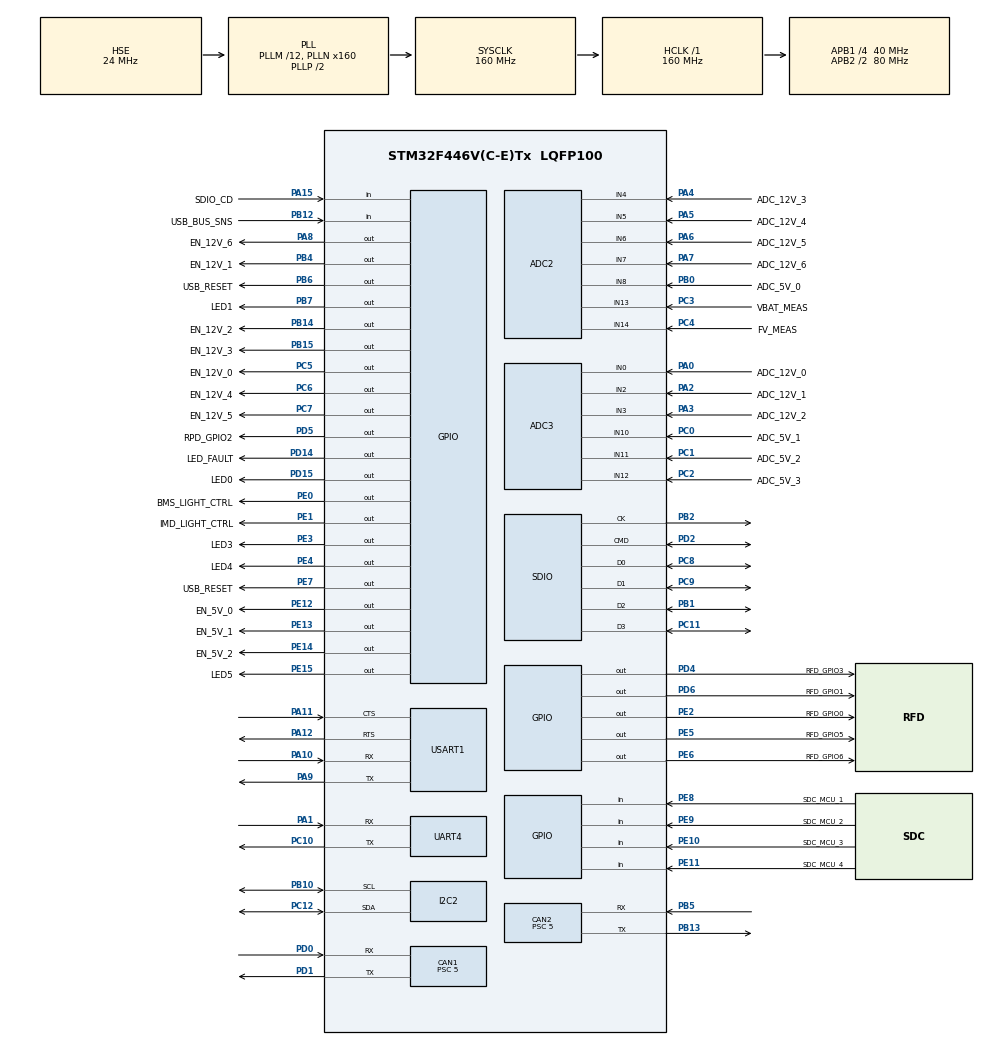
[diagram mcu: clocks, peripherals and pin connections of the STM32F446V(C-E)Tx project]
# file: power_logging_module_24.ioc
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ADC1.Channel-0\#ChannelRegularConversion=ADC_CHANNEL_TEMPSENSOR
ADC1.ClockPrescaler=ADC_CLOCK_SYNC_PCLK_DIV8
ADC1.ContinuousConvMode=ENABLE
ADC1.DMAContinuousRequests=ENABLE
ADC1.DiscontinuousConvMode=DISABLE
ADC1.ExternalTrigConv=ADC_EXTERNALTRIGCONV_T3_TRGO
ADC1.NbrOfConversionFlag=1
ADC1.Rank-0\#ChannelRegularConversion=1
ADC1.SamplingTime-0\#ChannelRegularConversion=ADC_SAMPLETIME_480CYCLES
ADC1.ScanConvMode=ENABLE
ADC1.master=1
ADC2.Channel-0\#ChannelRegularConversion=ADC_CHANNEL_4
ADC2.Channel-1\#ChannelRegularConversion=ADC_CHANNEL_5
ADC2.Channel-2\#ChannelRegularConversion=ADC_CHANNEL_6
ADC2.Channel-3\#ChannelRegularConversion=ADC_CHANNEL_7
ADC2.Channel-4\#ChannelRegularConversion=ADC_CHANNEL_8
ADC2.Channel-5\#ChannelRegularConversion=ADC_CHANNEL_13
ADC2.Channel-6\#ChannelRegularConversion=ADC_CHANNEL_14
ADC2.ClockPrescaler=ADC_CLOCK_SYNC_PCLK_DIV8
ADC2.ContinuousConvMode=ENABLE
ADC2.DMAContinuousRequests=ENABLE
ADC2.NbrOfConversion=7
ADC2.NbrOfConversionFlag=1
ADC2.Rank-0\#ChannelRegularConversion=1
ADC2.Rank-1\#ChannelRegularConversion=2
ADC2.Rank-2\#ChannelRegularConversion=3
ADC2.Rank-3\#ChannelRegularConversion=4
ADC2.Rank-4\#ChannelRegularConversion=5
ADC2.Rank-5\#ChannelRegularConversion=6
ADC2.Rank-6\#ChannelRegularConversion=7
ADC2.SamplingTime-0\#ChannelRegularConversion=ADC_SAMPLETIME_480CYCLES
ADC2.SamplingTime-1\#ChannelRegularConversion=ADC_SAMPLETIME_480CYCLES
ADC2.SamplingTime-2\#ChannelRegularConversion=ADC_SAMPLETIME_480CYCLES
ADC2.SamplingTime-3\#ChannelRegularConversion=ADC_SAMPLETIME_480CYCLES
ADC2.SamplingTime-4\#ChannelRegularConversion=ADC_SAMPLETIME_480CYCLES
ADC2.SamplingTime-5\#ChannelRegularConversion=ADC_SAMPLETIME_480CYCLES
ADC2.SamplingTime-6\#ChannelRegularConversion=ADC_SAMPLETIME_480CYCLES
ADC2.ScanConvMode=ENABLE
ADC3.Channel-0\#ChannelRegularConversion=ADC_CHANNEL_0
ADC3.Channel-1\#ChannelRegularConversion=ADC_CHANNEL_2
ADC3.Channel-2\#ChannelRegularConversion=ADC_CHANNEL_3
ADC3.Channel-3\#ChannelRegularConversion=ADC_CHANNEL_10
ADC3.Channel-4\#ChannelRegularConversion=ADC_CHANNEL_11
ADC3.Channel-5\#ChannelRegularConversion=ADC_CHANNEL_12
ADC3.ClockPrescaler=ADC_CLOCK_SYNC_PCLK_DIV8
ADC3.ContinuousConvMode=ENABLE
ADC3.DMAContinuousRequests=ENABLE
ADC3.NbrOfConversion=6
ADC3.NbrOfConversionFlag=1
ADC3.Rank-0\#ChannelRegularConversion=1
ADC3.Rank-1\#ChannelRegularConversion=2
ADC3.Rank-2\#ChannelRegularConversion=3
ADC3.Rank-3\#ChannelRegularConversion=4
ADC3.Rank-4\#ChannelRegularConversion=5
ADC3.Rank-5\#ChannelRegularConversion=6
ADC3.SamplingTime-0\#ChannelRegularConversion=ADC_SAMPLETIME_480CYCLES
ADC3.SamplingTime-1\#ChannelRegularConversion=ADC_SAMPLETIME_480CYCLES
ADC3.SamplingTime-2\#ChannelRegularConversion=ADC_SAMPLETIME_480CYCLES
ADC3.SamplingTime-3\#ChannelRegularConversion=ADC_SAMPLETIME_480CYCLES
ADC3.SamplingTime-4\#ChannelRegularConversion=ADC_SAMPLETIME_480CYCLES
ADC3.SamplingTime-5\#ChannelRegularConversion=ADC_SAMPLETIME_480CYCLES
ADC3.ScanConvMode=ENABLE
CAN1.ABOM=DISABLE
CAN1.AWUM=DISABLE
CAN1.BS1=CAN_BS1_6TQ
CAN1.CalculateBaudRate=1000000
CAN1.CalculateTimeBit=1000
CAN1.CalculateTimeQuantum=125.0
CAN1.Prescaler=5
CAN2.ABOM=DISABLE
CAN2.AWUM=DISABLE
CAN2.BS1=CAN_BS1_6TQ
CAN2.CalculateBaudRate=1000000
CAN2.CalculateTimeBit=1000
CAN2.CalculateTimeQuantum=125.0
CAN2.Prescaler=5
Dma.ADC1.2.Direction=DMA_PERIPH_TO_MEMORY
Dma.ADC1.2.FIFOMode=DMA_FIFOMODE_DISABLE
Dma.ADC1.2.Instance=DMA2_Stream0
Dma.ADC1.2.MemDataAlignment=DMA_MDATAALIGN_HALFWORD
Dma.ADC1.2.MemInc=DMA_MINC_ENABLE
Dma.ADC1.2.Mode=DMA_CIRCULAR
Dma.ADC1.2.PeriphDataAlignment=DMA_PDATAALIGN_HALFWORD
Dma.ADC1.2.PeriphInc=DMA_PINC_DISABLE
Dma.ADC1.2.Priority=DMA_PRIORITY_LOW
Dma.ADC2.0.Direction=DMA_PERIPH_TO_MEMORY
Dma.ADC2.0.FIFOMode=DMA_FIFOMODE_DISABLE
Dma.ADC2.0.Instance=DMA2_Stream2
Dma.ADC2.0.MemDataAlignment=DMA_MDATAALIGN_HALFWORD
Dma.ADC2.0.MemInc=DMA_MINC_ENABLE
Dma.ADC2.0.Mode=DMA_CIRCULAR
Dma.ADC2.0.PeriphDataAlignment=DMA_PDATAALIGN_HALFWORD
Dma.ADC2.0.PeriphInc=DMA_PINC_DISABLE
Dma.ADC2.0.Priority=DMA_PRIORITY_LOW
Dma.ADC3.1.Direction=DMA_PERIPH_TO_MEMORY
Dma.ADC3.1.FIFOMode=DMA_FIFOMODE_DISABLE
Dma.ADC3.1.Instance=DMA2_Stream1
Dma.ADC3.1.MemDataAlignment=DMA_MDATAALIGN_HALFWORD
Dma.ADC3.1.MemInc=DMA_MINC_ENABLE
Dma.ADC3.1.Mode=DMA_CIRCULAR
Dma.ADC3.1.PeriphDataAlignment=DMA_PDATAALIGN_HALFWORD
Dma.ADC3.1.PeriphInc=DMA_PINC_DISABLE
Dma.ADC3.1.Priority=DMA_PRIORITY_LOW
Dma.Request0=ADC2
Dma.Request1=ADC3
Dma.Request2=ADC1
Dma.Request3=SDIO_RX
Dma.Request4=SDIO_TX
Dma.SDIO_RX.3.Direction=DMA_PERIPH_TO_MEMORY
Dma.SDIO_RX.3.FIFOMode=DMA_FIFOMODE_ENABLE
Dma.SDIO_RX.3.FIFOThreshold=DMA_FIFO_THRESHOLD_FULL
Dma.SDIO_RX.3.Instance=DMA2_Stream3
Dma.SDIO_RX.3.MemBurst=DMA_MBURST_INC4
Dma.SDIO_RX.3.MemDataAlignment=DMA_MDATAALIGN_WORD
Dma.SDIO_RX.3.MemInc=DMA_MINC_ENABLE
Dma.SDIO_RX.3.Mode=DMA_PFCTRL
Dma.SDIO_RX.3.PeriphBurst=DMA_PBURST_INC4
Dma.SDIO_RX.3.PeriphDataAlignment=DMA_PDATAALIGN_WORD
Dma.SDIO_RX.3.PeriphInc=DMA_PINC_DISABLE
Dma.SDIO_RX.3.Priority=DMA_PRIORITY_LOW
Dma.SDIO_TX.4.Direction=DMA_MEMORY_TO_PERIPH
Dma.SDIO_TX.4.FIFOMode=DMA_FIFOMODE_ENABLE
Dma.SDIO_TX.4.FIFOThreshold=DMA_FIFO_THRESHOLD_FULL
Dma.SDIO_TX.4.Instance=DMA2_Stream6
Dma.SDIO_TX.4.MemBurst=DMA_MBURST_INC4
Dma.SDIO_TX.4.MemDataAlignment=DMA_MDATAALIGN_WORD
Dma.SDIO_TX.4.MemInc=DMA_MINC_ENABLE
Dma.SDIO_TX.4.Mode=DMA_PFCTRL
Dma.SDIO_TX.4.PeriphBurst=DMA_PBURST_INC4
Dma.SDIO_TX.4.PeriphDataAlignment=DMA_PDATAALIGN_WORD
Dma.SDIO_TX.4.PeriphInc=DMA_PINC_DISABLE
Dma.SDIO_TX.4.Priority=DMA_PRIORITY_LOW
FREERTOS.Tasks01=service_can,0,1024,plm_task_service_can,Default,NULL,Dynamic,NULL,NULL;store_data,0,1024,plm_task_store_data,Default,NULL,Dynamic,NULL,NULL;plm_heartbeat,-2,512,plm_task_heartbeat,Default,NULL,Dynamic,NULL,NULL;simulate_data,-2,512,plm_task_simulate_data,Default,NULL,Dynamic,NULL,NULL;collect_data,0,1024,plm_task_collect_data,Default,NULL,Dynamic,NULL,NULL;monitor_current,0,1024,plm_task_monitor_current,Default,NULL,Dynamic,NULL,NULL
FREERTOS.configENABLE_FPU=1
FREERTOS.configTOTAL_HEAP_SIZE=64000
FREERTOS.configUSE_NEWLIB_REENTRANT=1
Mcu.Family=STM32F4
Mcu.Name=STM32F446V(C-E)Tx
Mcu.Package=LQFP100
NVIC.ADC_IRQn=true\:5\:0\:true\:false\:true\:true\:true\:true\:true
NVIC.CAN1_RX0_IRQn=true\:5\:0\:true\:false\:true\:true\:true\:true\:true
NVIC.CAN1_RX1_IRQn=true\:5\:0\:true\:false\:true\:true\:true\:true\:true
NVIC.CAN1_TX_IRQn=true\:5\:0\:true\:false\:true\:true\:true\:true\:true
NVIC.CAN2_RX0_IRQn=true\:5\:0\:true\:false\:true\:true\:true\:true\:true
NVIC.CAN2_RX1_IRQn=true\:5\:0\:true\:false\:true\:true\:true\:true\:true
NVIC.CAN2_TX_IRQn=true\:5\:0\:true\:false\:true\:true\:true\:true\:true
NVIC.DMA2_Stream0_IRQn=true\:5\:0\:true\:false\:true\:true\:false\:true\:true
NVIC.DMA2_Stream1_IRQn=true\:5\:0\:true\:false\:true\:true\:false\:true\:true
NVIC.DMA2_Stream2_IRQn=true\:5\:0\:true\:false\:true\:true\:false\:true\:true
NVIC.DMA2_Stream3_IRQn=true\:5\:0\:false\:false\:true\:true\:false\:true\:true
NVIC.DMA2_Stream6_IRQn=true\:5\:0\:false\:false\:true\:true\:false\:true\:true
NVIC.PriorityGroup=NVIC_PRIORITYGROUP_4
NVIC.SDIO_IRQn=true\:5\:0\:false\:false\:true\:true\:true\:true\:true
NVIC.TIM1_UP_TIM10_IRQn=true\:5\:0\:false\:false\:true\:false\:false\:true\:true
NVIC.TIM6_DAC_IRQn=true\:15\:0\:false\:false\:true\:false\:false\:true\:true
NVIC.TimeBase=TIM6_DAC_IRQn
NVIC.TimeBaseIP=TIM6
PA0-WKUP.GPIO_Label=ADC_12V_0
PA0-WKUP.Signal=ADCx_IN0
PA1.Mode=Asynchronous
PA1.Signal=UART4_RX
PA10.Mode=Asynchronous
PA10.Signal=USART1_RX
PA11.Mode=CTS_RTS
PA11.Signal=USART1_CTS
PA12.Mode=CTS_RTS
PA12.Signal=USART1_RTS
PA13.Mode=Serial_Wire
PA13.Signal=SYS_JTMS-SWDIO
PA14.Mode=Serial_Wire
PA14.Signal=SYS_JTCK-SWCLK
PA15.GPIO_Label=SDIO_CD
PA15.Signal=GPIO_Input
PA2.GPIO_Label=ADC_12V_1
PA2.Signal=ADCx_IN2
PA3.GPIO_Label=ADC_12V_2
PA3.Signal=ADCx_IN3
PA4.GPIO_Label=ADC_12V_3
PA4.Signal=ADCx_IN4
PA5.GPIO_Label=ADC_12V_4
PA5.Signal=ADCx_IN5
PA6.GPIO_Label=ADC_12V_5
PA6.Signal=ADCx_IN6
PA7.GPIO_Label=ADC_12V_6
PA7.Signal=ADCx_IN7
PA8.GPIO_Label=EN_12V_6
PA8.Signal=GPIO_Output
PA9.Mode=Asynchronous
PA9.Signal=USART1_TX
PB0.GPIO_Label=ADC_5V_0
PB0.Signal=ADCx_IN8
PB1.Mode=SD_4_bits_Wide_bus
PB1.Signal=SDIO_D2
PB10.Mode=I2C
PB10.Signal=I2C2_SCL
PB12.GPIO_Label=USB_BUS_SNS
PB12.Signal=GPIO_Input
PB13.Mode=CAN_Activate
PB13.Signal=CAN2_TX
PB14.GPIO_Label=EN_12V_2
PB14.Signal=GPIO_Output
PB15.GPIO_Label=EN_12V_3
PB15.Signal=GPIO_Output
PB2.Mode=SD_4_bits_Wide_bus
PB2.Signal=SDIO_CK
PB3.Signal=SYS_JTDO-SWO
PB4.GPIO_Label=EN_12V_1
PB4.Signal=GPIO_Output
PB5.Mode=CAN_Activate
PB5.Signal=CAN2_RX
PB6.GPIO_Label=USB_RESET
PB6.Signal=GPIO_Output
PB7.GPIO_Label=LED1
PB7.Signal=GPIO_Output
PC0.GPIO_Label=ADC_5V_1
PC0.Signal=ADCx_IN10
PC1.GPIO_Label=ADC_5V_2
PC1.Signal=ADCx_IN11
PC10.Mode=Asynchronous
PC10.Signal=UART4_TX
PC11.Mode=SD_4_bits_Wide_bus
PC11.Signal=SDIO_D3
PC12.Mode=I2C
PC12.Signal=I2C2_SDA
PC14-OSC32_IN.Mode=LSE-External-Clock-Source
PC14-OSC32_IN.Signal=RCC_OSC32_IN
PC15-OSC32_OUT.Mode=LSE-External-Clock-Source
PC15-OSC32_OUT.Signal=RCC_OSC32_OUT
PC2.GPIO_Label=ADC_5V_3
PC2.Signal=ADCx_IN12
PC3.GPIO_Label=VBAT_MEAS
PC3.Signal=ADCx_IN13
PC4.GPIO_Label=FV_MEAS
PC4.Signal=ADCx_IN14
PC5.GPIO_Label=EN_12V_0
PC5.Signal=GPIO_Output
PC6.GPIO_Label=EN_12V_4
PC6.Signal=GPIO_Output
PC7.GPIO_Label=EN_12V_5
PC7.Signal=GPIO_Output
PC8.GPIO_PuPd=GPIO_PULLUP
PC8.Mode=SD_4_bits_Wide_bus
PC8.Signal=SDIO_D0
PC9.Mode=SD_4_bits_Wide_bus
PC9.Signal=SDIO_D1
PD0.Mode=CAN_Activate
PD0.Signal=CAN1_RX
PD1.Mode=CAN_Activate
PD1.Signal=CAN1_TX
PD14.GPIO_Label=LED_FAULT
PD14.Signal=GPIO_Output
PD15.GPIO_Label=LED0
PD15.Signal=GPIO_Output
PD2.GPIO_PuPd=GPIO_PULLUP
PD2.Mode=SD_4_bits_Wide_bus
PD2.Signal=SDIO_CMD
PD4.GPIO_Label=RFD_GPIO3
PD4.Signal=GPIO_Output
PD5.GPIO_Label=RPD_GPIO2
PD5.Signal=GPIO_Output
PD6.GPIO_Label=RFD_GPIO1
PD6.Signal=GPIO_Output
PE0.GPIO_Label=BMS_LIGHT_CTRL
PE0.Signal=GPIO_Output
PE1.GPIO_Label=IMD_LIGHT_CTRL
PE1.Signal=GPIO_Output
PE10.GPIO_Label=SDC_MCU_3
PE10.Signal=GPIO_Input
PE11.GPIO_Label=SDC_MCU_4
PE11.Signal=GPIO_Input
PE12.GPIO_Label=EN_5V_0
PE12.Signal=GPIO_Output
PE13.GPIO_Label=EN_5V_1
PE13.Signal=GPIO_Output
PE14.GPIO_Label=EN_5V_2
PE14.Signal=GPIO_Output
PE15.GPIO_Label=LED5
PE15.Signal=GPIO_Output
PE2.GPIO_Label=RFD_GPIO0
PE2.Signal=GPIO_Output
PE3.GPIO_Label=LED3
PE3.Signal=GPIO_Output
PE4.GPIO_Label=LED4
PE4.Signal=GPIO_Output
PE5.GPIO_Label=RFD_GPIO5
PE5.Signal=GPIO_Output
PE6.GPIO_Label=RFD_GPIO6
PE6.Signal=GPIO_Output
PE7.GPIO_Label=USB_RESET
PE7.Signal=GPIO_Output
PE8.GPIO_Label=SDC_MCU_1
PE8.Signal=GPIO_Input
PE9.GPIO_Label=SDC_MCU_2
PE9.Signal=GPIO_Input
PH0-OSC_IN.Mode=HSE-External-Clock-Source
PH0-OSC_IN.Signal=RCC_OSC_IN
PH1-OSC_OUT.Mode=HSE-External-Clock-Source
PH1-OSC_OUT.Signal=RCC_OSC_OUT
ProjectManager.HeapSize=0x80
ProjectManager.StackSize=0x400
ProjectManager.TargetToolchain=STM32CubeIDE
RCC.AHBFreq_Value=160000000
RCC.APB1CLKDivider=RCC_HCLK_DIV4
RCC.APB1Freq_Value=40000000
RCC.APB1TimFreq_Value=80000000
RCC.APB2CLKDivider=RCC_HCLK_DIV2
RCC.APB2Freq_Value=80000000
RCC.APB2TimFreq_Value=160000000
RCC.CortexFreq_Value=160000000
RCC.HCLKFreq_Value=160000000
RCC.HSE_VALUE=24000000
RCC.PLLM=12
RCC.PLLN=160
RCC.PLLQ=7
RCC.PLLSourceVirtual=RCC_PLLSOURCE_HSE
RCC.RCC_RTC_Clock_SourceVirtual=RCC_RTCCLKSOURCE_LSE
RCC.SYSCLKFreq_VALUE=160000000
RCC.SYSCLKSource=RCC_SYSCLKSOURCE_PLLCLK
RCC.USBFreq_Value=45714285.71428572
RCC.VCOOutputFreq_Value=320000000
SH.ADCx_IN0.0=ADC3_IN0,IN0
SH.ADCx_IN10.0=ADC3_IN10,IN10
SH.ADCx_IN11.0=ADC3_IN11,IN11
SH.ADCx_IN12.0=ADC3_IN12,IN12
SH.ADCx_IN13.0=ADC2_IN13,IN13
SH.ADCx_IN14.0=ADC2_IN14,IN14
SH.ADCx_IN2.0=ADC3_IN2,IN2
SH.ADCx_IN3.0=ADC3_IN3,IN3
SH.ADCx_IN4.0=ADC2_IN4,IN4
SH.ADCx_IN5.0=ADC2_IN5,IN5
SH.ADCx_IN6.0=ADC2_IN6,IN6
SH.ADCx_IN7.0=ADC2_IN7,IN7
SH.ADCx_IN8.0=ADC2_IN8,IN8
TIM3.Period=10000-1
TIM3.Prescaler=840-1
TIM3.TIM_MasterOutputTrigger=TIM_TRGO_UPDATE
UART4.VirtualMode=Asynchronous
USART1.VirtualMode=VM_ASYNC
VP_ADC1_TempSens_Input.Mode=IN-TempSens
VP_FREERTOS_VS_CMSIS_V1.Mode=CMSIS_V1
VP_RTC_VS_RTC_Activate.Mode=RTC_Enabled
VP_SYS_VS_tim6.Mode=TIM6
VP_TIM10_VS_ClockSourceINT.Mode=Enable_Timer
VP_TIM3_VS_ClockSourceINT.Mode=Internal
board=custom

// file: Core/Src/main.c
/* USER CODE BEGIN Header */
/**
  ******************************************************************************
  * @file           : main.c
  * @brief          : Main program body
  ******************************************************************************
  * @attention
  *
  * Copyright (c) 2024 STMicroelectronics.
  * All rights reserved.
  *
  * This software is licensed under terms that can be found in the LICENSE file
  * in the root directory of this software component.
  * If no LICENSE file comes with this software, it is provided AS-IS.
  *
  ******************************************************************************
  */
/* USER CODE END Header */
#include "main.h"
#include "cmsis_os.h"
#include "fatfs.h"

/* USER CODE BEGIN Includes */
#include <stdio.h>
#include "plm.h"
#include "adc_lib.h"
#include "plm_error.h"
/* USER CODE END Includes */

ADC_HandleTypeDef hadc1;
ADC_HandleTypeDef hadc2;
ADC_HandleTypeDef hadc3;
DMA_HandleTypeDef hdma_adc1;
DMA_HandleTypeDef hdma_adc2;
DMA_HandleTypeDef hdma_adc3;

CAN_HandleTypeDef hcan1;
CAN_HandleTypeDef hcan2;

I2C_HandleTypeDef hi2c2;

RTC_HandleTypeDef hrtc;

SD_HandleTypeDef hsd;
DMA_HandleTypeDef hdma_sdio_rx;
DMA_HandleTypeDef hdma_sdio_tx;

TIM_HandleTypeDef htim3;
TIM_HandleTypeDef htim10;

UART_HandleTypeDef huart4;
UART_HandleTypeDef huart1;

osThreadId service_canHandle;
osThreadId store_dataHandle;
osThreadId plm_heartbeatHandle;
osThreadId simulate_dataHandle;
osThreadId collect_dataHandle;
osThreadId monitor_currentHandle;

void SystemClock_Config(void);
static void MX_GPIO_Init(void);
static void MX_DMA_Init(void);
static void MX_ADC1_Init(void);
static void MX_ADC2_Init(void);
static void MX_ADC3_Init(void);
static void MX_CAN1_Init(void);
static void MX_CAN2_Init(void);
static void MX_I2C2_Init(void);
static void MX_RTC_Init(void);
static void MX_SDIO_SD_Init(void);
static void MX_UART4_Init(void);
static void MX_USART1_UART_Init(void);
static void MX_TIM3_Init(void);
static void MX_TIM10_Init(void);
void plm_task_service_can(void const * argument);
void plm_task_store_data(void const * argument);
void plm_task_heartbeat(void const * argument);
void plm_task_simulate_data(void const * argument);
void plm_task_collect_data(void const * argument);
void plm_task_monitor_current(void const * argument);

/* USER CODE BEGIN PFP */
// redirect printf to USART (STLink Virtual COM)
// NOTE: output gets flushed at newline \n
#ifdef __GNUC__
#define PUTCHAR_PROTOTYPE int __io_putchar(int ch)
#else
#define PUTCHAR_PROTOTYPE int fputc(int ch, FILE *f)
#endif

PUTCHAR_PROTOTYPE
{
  HAL_UART_Transmit(&huart4, (uint8_t*)&ch, 1, HAL_MAX_DELAY);
  HAL_UART_Transmit(&huart4, (uint8_t*)&ch, 1, HAL_MAX_DELAY);
  return ch;
}
/* USER CODE END PFP */

int main(void)
{

  /* MCU Configuration--------------------------------------------------------*/

  /* Reset of all peripherals, Initializes the Flash interface and the Systick. */
  HAL_Init();

  /* Configure the system clock */
  SystemClock_Config();

  /* USER CODE BEGIN SysInit */
  MX_DMA_Init();
  /* USER CODE END SysInit */

  /* Initialize all configured peripherals */
  MX_GPIO_Init();
  MX_DMA_Init();
  MX_ADC1_Init();
  MX_ADC2_Init();
  MX_ADC3_Init();
  MX_CAN1_Init();
  MX_CAN2_Init();
  MX_I2C2_Init();
  MX_RTC_Init();
  MX_SDIO_SD_Init();
  MX_UART4_Init();
  MX_USART1_UART_Init();
  MX_TIM3_Init();
  MX_TIM10_Init();
  MX_FATFS_Init();
  /* USER CODE BEGIN 2 */
  plm_init();
  /* USER CODE END 2 */

  /* Create the thread(s) */
  /* definition and creation of service_can */
  osThreadDef(service_can, plm_task_service_can, osPriorityNormal, 0, 1024);
  service_canHandle = osThreadCreate(osThread(service_can), NULL);

  /* definition and creation of store_data */
  osThreadDef(store_data, plm_task_store_data, osPriorityNormal, 0, 1024);
  store_dataHandle = osThreadCreate(osThread(store_data), NULL);

  /* definition and creation of plm_heartbeat */
  osThreadDef(plm_heartbeat, plm_task_heartbeat, osPriorityLow, 0, 512);
  plm_heartbeatHandle = osThreadCreate(osThread(plm_heartbeat), NULL);

  /* definition and creation of simulate_data */
  osThreadDef(simulate_data, plm_task_simulate_data, osPriorityLow, 0, 512);
  simulate_dataHandle = osThreadCreate(osThread(simulate_data), NULL);

  /* definition and creation of collect_data */
  osThreadDef(collect_data, plm_task_collect_data, osPriorityNormal, 0, 1024);
  collect_dataHandle = osThreadCreate(osThread(collect_data), NULL);

  /* definition and creation of monitor_current */
  osThreadDef(monitor_current, plm_task_monitor_current, osPriorityNormal, 0, 1024);
  monitor_currentHandle = osThreadCreate(osThread(monitor_current), NULL);

  /* Start scheduler */
  osKernelStart();

  /* We should never get here as control is now taken by the scheduler */

  /* Infinite loop */
  while (1)
  {

  }
}

void SystemClock_Config(void)
{
  RCC_OscInitTypeDef RCC_OscInitStruct = {0};
  RCC_ClkInitTypeDef RCC_ClkInitStruct = {0};

  /** Configure the main internal regulator output voltage
  */
  __HAL_RCC_PWR_CLK_ENABLE();
  __HAL_PWR_VOLTAGESCALING_CONFIG(PWR_REGULATOR_VOLTAGE_SCALE1);

  /** Initializes the RCC Oscillators according to the specified parameters
  * in the RCC_OscInitTypeDef structure.
  */
  RCC_OscInitStruct.OscillatorType = RCC_OSCILLATORTYPE_HSE|RCC_OSCILLATORTYPE_LSE;
  RCC_OscInitStruct.HSEState = RCC_HSE_BYPASS;
  RCC_OscInitStruct.LSEState = RCC_LSE_BYPASS;
  RCC_OscInitStruct.PLL.PLLState = RCC_PLL_ON;
  RCC_OscInitStruct.PLL.PLLSource = RCC_PLLSOURCE_HSE;
  RCC_OscInitStruct.PLL.PLLM = 12;
  RCC_OscInitStruct.PLL.PLLN = 160;
  RCC_OscInitStruct.PLL.PLLP = RCC_PLLP_DIV2;
  RCC_OscInitStruct.PLL.PLLQ = 7;
  RCC_OscInitStruct.PLL.PLLR = 2;
  if (HAL_RCC_OscConfig(&RCC_OscInitStruct) != HAL_OK)
  {
    Error_Handler();
  }

  /** Initializes the CPU, AHB and APB buses clocks
  */
  RCC_ClkInitStruct.ClockType = RCC_CLOCKTYPE_HCLK|RCC_CLOCKTYPE_SYSCLK
                              |RCC_CLOCKTYPE_PCLK1|RCC_CLOCKTYPE_PCLK2;
  RCC_ClkInitStruct.SYSCLKSource = RCC_SYSCLKSOURCE_PLLCLK;
  RCC_ClkInitStruct.AHBCLKDivider = RCC_SYSCLK_DIV1;
  RCC_ClkInitStruct.APB1CLKDivider = RCC_HCLK_DIV4;
  RCC_ClkInitStruct.APB2CLKDivider = RCC_HCLK_DIV2;

  if (HAL_RCC_ClockConfig(&RCC_ClkInitStruct, FLASH_LATENCY_5) != HAL_OK)
  {
    Error_Handler();
  }
}

static void MX_ADC1_Init(void)
{

  ADC_ChannelConfTypeDef sConfig = {0};

  /** Configure the global features of the ADC (Clock, Resolution, Data Alignment and number of conversion)
  */
  hadc1.Instance = ADC1;
  hadc1.Init.ClockPrescaler = ADC_CLOCK_SYNC_PCLK_DIV8;
  hadc1.Init.Resolution = ADC_RESOLUTION_12B;
  hadc1.Init.ScanConvMode = ENABLE;
  hadc1.Init.ContinuousConvMode = ENABLE;
  hadc1.Init.DiscontinuousConvMode = DISABLE;
  hadc1.Init.ExternalTrigConvEdge = ADC_EXTERNALTRIGCONVEDGE_RISING;
  hadc1.Init.ExternalTrigConv = ADC_EXTERNALTRIGCONV_T3_TRGO;
  hadc1.Init.DataAlign = ADC_DATAALIGN_RIGHT;
  hadc1.Init.NbrOfConversion = 1;
  hadc1.Init.DMAContinuousRequests = ENABLE;
  hadc1.Init.EOCSelection = ADC_EOC_SINGLE_CONV;
  if (HAL_ADC_Init(&hadc1) != HAL_OK)
  {
    Error_Handler();
  }

  /** Configure for the selected ADC regular channel its corresponding rank in the sequencer and its sample time.
  */
  sConfig.Channel = ADC_CHANNEL_TEMPSENSOR;
  sConfig.Rank = 1;
  sConfig.SamplingTime = ADC_SAMPLETIME_480CYCLES;
  if (HAL_ADC_ConfigChannel(&hadc1, &sConfig) != HAL_OK)
  {
    Error_Handler();
  }

}

static void MX_ADC2_Init(void)
{

  ADC_ChannelConfTypeDef sConfig = {0};

  /** Configure the global features of the ADC (Clock, Resolution, Data Alignment and number of conversion)
  */
  hadc2.Instance = ADC2;
  hadc2.Init.ClockPrescaler = ADC_CLOCK_SYNC_PCLK_DIV8;
  hadc2.Init.Resolution = ADC_RESOLUTION_12B;
  hadc2.Init.ScanConvMode = ENABLE;
  hadc2.Init.ContinuousConvMode = ENABLE;
  hadc2.Init.DiscontinuousConvMode = DISABLE;
  hadc2.Init.ExternalTrigConvEdge = ADC_EXTERNALTRIGCONVEDGE_NONE;
  hadc2.Init.ExternalTrigConv = ADC_SOFTWARE_START;
  hadc2.Init.DataAlign = ADC_DATAALIGN_RIGHT;
  hadc2.Init.NbrOfConversion = 7;
  hadc2.Init.DMAContinuousRequests = ENABLE;
  hadc2.Init.EOCSelection = ADC_EOC_SINGLE_CONV;
  if (HAL_ADC_Init(&hadc2) != HAL_OK)
  {
    Error_Handler();
  }

  /** Configure for the selected ADC regular channel its corresponding rank in the sequencer and its sample time.
  */
  sConfig.Channel = ADC_CHANNEL_4;
  sConfig.Rank = 1;
  sConfig.SamplingTime = ADC_SAMPLETIME_480CYCLES;
  if (HAL_ADC_ConfigChannel(&hadc2, &sConfig) != HAL_OK)
  {
    Error_Handler();
  }

  /** Configure for the selected ADC regular channel its corresponding rank in the sequencer and its sample time.
  */
  sConfig.Channel = ADC_CHANNEL_5;
  sConfig.Rank = 2;
  if (HAL_ADC_ConfigChannel(&hadc2, &sConfig) != HAL_OK)
  {
    Error_Handler();
  }

  /** Configure for the selected ADC regular channel its corresponding rank in the sequencer and its sample time.
  */
  sConfig.Channel = ADC_CHANNEL_6;
  sConfig.Rank = 3;
  if (HAL_ADC_ConfigChannel(&hadc2, &sConfig) != HAL_OK)
  {
    Error_Handler();
  }

  /** Configure for the selected ADC regular channel its corresponding rank in the sequencer and its sample time.
  */
  sConfig.Channel = ADC_CHANNEL_7;
  sConfig.Rank = 4;
  if (HAL_ADC_ConfigChannel(&hadc2, &sConfig) != HAL_OK)
  {
    Error_Handler();
  }

  /** Configure for the selected ADC regular channel its corresponding rank in the sequencer and its sample time.
  */
  sConfig.Channel = ADC_CHANNEL_8;
  sConfig.Rank = 5;
  if (HAL_ADC_ConfigChannel(&hadc2, &sConfig) != HAL_OK)
  {
    Error_Handler();
  }

  /** Configure for the selected ADC regular channel its corresponding rank in the sequencer and its sample time.
  */
  sConfig.Channel = ADC_CHANNEL_13;
  sConfig.Rank = 6;
  if (HAL_ADC_ConfigChannel(&hadc2, &sConfig) != HAL_OK)
  {
    Error_Handler();
  }

  /** Configure for the selected ADC regular channel its corresponding rank in the sequencer and its sample time.
  */
  sConfig.Channel = ADC_CHANNEL_14;
  sConfig.Rank = 7;
  if (HAL_ADC_ConfigChannel(&hadc2, &sConfig) != HAL_OK)
  {
    Error_Handler();
  }

}

static void MX_ADC3_Init(void)
{

  ADC_ChannelConfTypeDef sConfig = {0};

  /** Configure the global features of the ADC (Clock, Resolution, Data Alignment and number of conversion)
  */
  hadc3.Instance = ADC3;
  hadc3.Init.ClockPrescaler = ADC_CLOCK_SYNC_PCLK_DIV8;
  hadc3.Init.Resolution = ADC_RESOLUTION_12B;
  hadc3.Init.ScanConvMode = ENABLE;
  hadc3.Init.ContinuousConvMode = ENABLE;
  hadc3.Init.DiscontinuousConvMode = DISABLE;
  hadc3.Init.ExternalTrigConvEdge = ADC_EXTERNALTRIGCONVEDGE_NONE;
  hadc3.Init.ExternalTrigConv = ADC_SOFTWARE_START;
  hadc3.Init.DataAlign = ADC_DATAALIGN_RIGHT;
  hadc3.Init.NbrOfConversion = 6;
  hadc3.Init.DMAContinuousRequests = ENABLE;
  hadc3.Init.EOCSelection = ADC_EOC_SINGLE_CONV;
  if (HAL_ADC_Init(&hadc3) != HAL_OK)
  {
    Error_Handler();
  }

  /** Configure for the selected ADC regular channel its corresponding rank in the sequencer and its sample time.
  */
  sConfig.Channel = ADC_CHANNEL_0;
  sConfig.Rank = 1;
  sConfig.SamplingTime = ADC_SAMPLETIME_480CYCLES;
  if (HAL_ADC_ConfigChannel(&hadc3, &sConfig) != HAL_OK)
  {
    Error_Handler();
  }

  /** Configure for the selected ADC regular channel its corresponding rank in the sequencer and its sample time.
  */
  sConfig.Channel = ADC_CHANNEL_2;
  sConfig.Rank = 2;
  if (HAL_ADC_ConfigChannel(&hadc3, &sConfig) != HAL_OK)
  {
    Error_Handler();
  }

  /** Configure for the selected ADC regular channel its corresponding rank in the sequencer and its sample time.
  */
  sConfig.Channel = ADC_CHANNEL_3;
  sConfig.Rank = 3;
  if (HAL_ADC_ConfigChannel(&hadc3, &sConfig) != HAL_OK)
  {
    Error_Handler();
  }

  /** Configure for the selected ADC regular channel its corresponding rank in the sequencer and its sample time.
  */
  sConfig.Channel = ADC_CHANNEL_10;
  sConfig.Rank = 4;
  if (HAL_ADC_ConfigChannel(&hadc3, &sConfig) != HAL_OK)
  {
    Error_Handler();
  }

  /** Configure for the selected ADC regular channel its corresponding rank in the sequencer and its sample time.
  */
  sConfig.Channel = ADC_CHANNEL_11;
  sConfig.Rank = 5;
  if (HAL_ADC_ConfigChannel(&hadc3, &sConfig) != HAL_OK)
  {
    Error_Handler();
  }

  /** Configure for the selected ADC regular channel its corresponding rank in the sequencer and its sample time.
  */
  sConfig.Channel = ADC_CHANNEL_12;
  sConfig.Rank = 6;
  if (HAL_ADC_ConfigChannel(&hadc3, &sConfig) != HAL_OK)
  {
    Error_Handler();
  }

}

static void MX_CAN1_Init(void)
{

  hcan1.Instance = CAN1;
  hcan1.Init.Prescaler = 5;
  hcan1.Init.Mode = CAN_MODE_NORMAL;
  hcan1.Init.SyncJumpWidth = CAN_SJW_1TQ;
  hcan1.Init.TimeSeg1 = CAN_BS1_6TQ;
  hcan1.Init.TimeSeg2 = CAN_BS2_1TQ;
  hcan1.Init.TimeTriggeredMode = DISABLE;
  hcan1.Init.AutoBusOff = DISABLE;
  hcan1.Init.AutoWakeUp = DISABLE;
  hcan1.Init.AutoRetransmission = DISABLE;
  hcan1.Init.ReceiveFifoLocked = DISABLE;
  hcan1.Init.TransmitFifoPriority = DISABLE;
  if (HAL_CAN_Init(&hcan1) != HAL_OK)
  {
    Error_Handler();
  }

}

static void MX_CAN2_Init(void)
{

  hcan2.Instance = CAN2;
  hcan2.Init.Prescaler = 5;
  hcan2.Init.Mode = CAN_MODE_NORMAL;
  hcan2.Init.SyncJumpWidth = CAN_SJW_1TQ;
  hcan2.Init.TimeSeg1 = CAN_BS1_6TQ;
  hcan2.Init.TimeSeg2 = CAN_BS2_1TQ;
  hcan2.Init.TimeTriggeredMode = DISABLE;
  hcan2.Init.AutoBusOff = DISABLE;
  hcan2.Init.AutoWakeUp = DISABLE;
  hcan2.Init.AutoRetransmission = DISABLE;
  hcan2.Init.ReceiveFifoLocked = DISABLE;
  hcan2.Init.TransmitFifoPriority = DISABLE;
  if (HAL_CAN_Init(&hcan2) != HAL_OK)
  {
    Error_Handler();
  }

}

static void MX_I2C2_Init(void)
{

  hi2c2.Instance = I2C2;
  hi2c2.Init.ClockSpeed = 100000;
  hi2c2.Init.DutyCycle = I2C_DUTYCYCLE_2;
  hi2c2.Init.OwnAddress1 = 0;
  hi2c2.Init.AddressingMode = I2C_ADDRESSINGMODE_7BIT;
  hi2c2.Init.DualAddressMode = I2C_DUALADDRESS_DISABLE;
  hi2c2.Init.OwnAddress2 = 0;
  hi2c2.Init.GeneralCallMode = I2C_GENERALCALL_DISABLE;
  hi2c2.Init.NoStretchMode = I2C_NOSTRETCH_DISABLE;
  if (HAL_I2C_Init(&hi2c2) != HAL_OK)
  {
    Error_Handler();
  }

}

static void MX_RTC_Init(void)
{

  /** Initialize RTC Only
  */
  hrtc.Instance = RTC;
  hrtc.Init.HourFormat = RTC_HOURFORMAT_24;
  hrtc.Init.AsynchPrediv = 127;
  hrtc.Init.SynchPrediv = 255;
  hrtc.Init.OutPut = RTC_OUTPUT_DISABLE;
  hrtc.Init.OutPutPolarity = RTC_OUTPUT_POLARITY_HIGH;
  hrtc.Init.OutPutType = RTC_OUTPUT_TYPE_OPENDRAIN;
  if (HAL_RTC_Init(&hrtc) != HAL_OK)
  {
    Error_Handler();
  }

}

static void MX_SDIO_SD_Init(void)
{

  hsd.Instance = SDIO;
  hsd.Init.ClockEdge = SDIO_CLOCK_EDGE_RISING;
  hsd.Init.ClockBypass = SDIO_CLOCK_BYPASS_DISABLE;
  hsd.Init.ClockPowerSave = SDIO_CLOCK_POWER_SAVE_DISABLE;
  hsd.Init.BusWide = SDIO_BUS_WIDE_4B;
  hsd.Init.HardwareFlowControl = SDIO_HARDWARE_FLOW_CONTROL_DISABLE;
  hsd.Init.ClockDiv = 0;

}

static void MX_TIM3_Init(void)
{

  TIM_ClockConfigTypeDef sClockSourceConfig = {0};
  TIM_MasterConfigTypeDef sMasterConfig = {0};

  htim3.Instance = TIM3;
  htim3.Init.Prescaler = 840-1;
  htim3.Init.CounterMode = TIM_COUNTERMODE_UP;
  htim3.Init.Period = 10000-1;
  htim3.Init.ClockDivision = TIM_CLOCKDIVISION_DIV1;
  htim3.Init.AutoReloadPreload = TIM_AUTORELOAD_PRELOAD_DISABLE;
  if (HAL_TIM_Base_Init(&htim3) != HAL_OK)
  {
    Error_Handler();
  }
  sClockSourceConfig.ClockSource = TIM_CLOCKSOURCE_INTERNAL;
  if (HAL_TIM_ConfigClockSource(&htim3, &sClockSourceConfig) != HAL_OK)
  {
    Error_Handler();
  }
  sMasterConfig.MasterOutputTrigger = TIM_TRGO_UPDATE;
  sMasterConfig.MasterSlaveMode = TIM_MASTERSLAVEMODE_DISABLE;
  if (HAL_TIMEx_MasterConfigSynchronization(&htim3, &sMasterConfig) != HAL_OK)
  {
    Error_Handler();
  }

}

static void MX_TIM10_Init(void)
{

  htim10.Instance = TIM10;
  htim10.Init.Prescaler = 0;
  htim10.Init.CounterMode = TIM_COUNTERMODE_UP;
  htim10.Init.Period = 65535;
  htim10.Init.ClockDivision = TIM_CLOCKDIVISION_DIV1;
  htim10.Init.AutoReloadPreload = TIM_AUTORELOAD_PRELOAD_DISABLE;
  if (HAL_TIM_Base_Init(&htim10) != HAL_OK)
  {
    Error_Handler();
  }

}

static void MX_UART4_Init(void)
{

  huart4.Instance = UART4;
  huart4.Init.BaudRate = 115200;
  huart4.Init.WordLength = UART_WORDLENGTH_8B;
  huart4.Init.StopBits = UART_STOPBITS_1;
  huart4.Init.Parity = UART_PARITY_NONE;
  huart4.Init.Mode = UART_MODE_TX_RX;
  huart4.Init.HwFlowCtl = UART_HWCONTROL_NONE;
  huart4.Init.OverSampling = UART_OVERSAMPLING_16;
  if (HAL_UART_Init(&huart4) != HAL_OK)
  {
    Error_Handler();
  }

}

static void MX_USART1_UART_Init(void)
{

  huart1.Instance = USART1;
  huart1.Init.BaudRate = 115200;
  huart1.Init.WordLength = UART_WORDLENGTH_8B;
  huart1.Init.StopBits = UART_STOPBITS_1;
  huart1.Init.Parity = UART_PARITY_NONE;
  huart1.Init.Mode = UART_MODE_TX_RX;
  huart1.Init.HwFlowCtl = UART_HWCONTROL_RTS_CTS;
  huart1.Init.OverSampling = UART_OVERSAMPLING_16;
  if (HAL_UART_Init(&huart1) != HAL_OK)
  {
    Error_Handler();
  }

}

static void MX_DMA_Init(void)
{

  /* DMA controller clock enable */
  __HAL_RCC_DMA2_CLK_ENABLE();

  /* DMA interrupt init */
  /* DMA2_Stream0_IRQn interrupt configuration */
  HAL_NVIC_SetPriority(DMA2_Stream0_IRQn, 5, 0);
  HAL_NVIC_EnableIRQ(DMA2_Stream0_IRQn);
  /* DMA2_Stream1_IRQn interrupt configuration */
  HAL_NVIC_SetPriority(DMA2_Stream1_IRQn, 5, 0);
  HAL_NVIC_EnableIRQ(DMA2_Stream1_IRQn);
  /* DMA2_Stream2_IRQn interrupt configuration */
  HAL_NVIC_SetPriority(DMA2_Stream2_IRQn, 5, 0);
  HAL_NVIC_EnableIRQ(DMA2_Stream2_IRQn);
  /* DMA2_Stream3_IRQn interrupt configuration */
  HAL_NVIC_SetPriority(DMA2_Stream3_IRQn, 5, 0);
  HAL_NVIC_EnableIRQ(DMA2_Stream3_IRQn);
  /* DMA2_Stream6_IRQn interrupt configuration */
  HAL_NVIC_SetPriority(DMA2_Stream6_IRQn, 5, 0);
  HAL_NVIC_EnableIRQ(DMA2_Stream6_IRQn);

}

static void MX_GPIO_Init(void)
{
  GPIO_InitTypeDef GPIO_InitStruct = {0};

  /* GPIO Ports Clock Enable */
  __HAL_RCC_GPIOE_CLK_ENABLE();
  __HAL_RCC_GPIOC_CLK_ENABLE();
  __HAL_RCC_GPIOH_CLK_ENABLE();
  __HAL_RCC_GPIOA_CLK_ENABLE();
  __HAL_RCC_GPIOB_CLK_ENABLE();
  __HAL_RCC_GPIOD_CLK_ENABLE();

  /*Configure GPIO pin Output Level */
  HAL_GPIO_WritePin(GPIOE, RFD_GPIO0_Pin|LED3_Pin|LED4_Pin|RFD_GPIO5_Pin
                          |RFD_GPIO6_Pin|USB_RESET_Pin|EN_5V_0_Pin|EN_5V_1_Pin
                          |EN_5V_2_Pin|LED5_Pin|BMS_LIGHT_CTRL_Pin|IMD_LIGHT_CTRL_Pin, GPIO_PIN_RESET);

  /*Configure GPIO pin Output Level */
  HAL_GPIO_WritePin(GPIOC, EN_12V_0_Pin|EN_12V_4_Pin|EN_12V_5_Pin, GPIO_PIN_RESET);

  /*Configure GPIO pin Output Level */
  HAL_GPIO_WritePin(GPIOB, EN_12V_2_Pin|EN_12V_3_Pin|EN_12V_1_Pin|USB_RESETB6_Pin
                          |LED1_Pin|GPIO_PIN_8|GPIO_PIN_9, GPIO_PIN_RESET);

  /*Configure GPIO pin Output Level */
  HAL_GPIO_WritePin(GPIOD, LED_FAULT_Pin|LED0_Pin|RFD_GPIO3_Pin|RPD_GPIO2_Pin
                          |RFD_GPIO1_Pin, GPIO_PIN_RESET);

  /*Configure GPIO pin Output Level */
  HAL_GPIO_WritePin(EN_12V_6_GPIO_Port, EN_12V_6_Pin, GPIO_PIN_RESET);

  /*Configure GPIO pins : RFD_GPIO0_Pin LED3_Pin LED4_Pin RFD_GPIO5_Pin
                           RFD_GPIO6_Pin USB_RESET_Pin EN_5V_0_Pin EN_5V_1_Pin
                           EN_5V_2_Pin LED5_Pin BMS_LIGHT_CTRL_Pin IMD_LIGHT_CTRL_Pin */
  GPIO_InitStruct.Pin = RFD_GPIO0_Pin|LED3_Pin|LED4_Pin|RFD_GPIO5_Pin
                          |RFD_GPIO6_Pin|USB_RESET_Pin|EN_5V_0_Pin|EN_5V_1_Pin
                          |EN_5V_2_Pin|LED5_Pin|BMS_LIGHT_CTRL_Pin|IMD_LIGHT_CTRL_Pin;
  GPIO_InitStruct.Mode = GPIO_MODE_OUTPUT_PP;
  GPIO_InitStruct.Pull = GPIO_NOPULL;
  GPIO_InitStruct.Speed = GPIO_SPEED_FREQ_LOW;
  HAL_GPIO_Init(GPIOE, &GPIO_InitStruct);

  /*Configure GPIO pins : EN_12V_0_Pin EN_12V_4_Pin EN_12V_5_Pin */
  GPIO_InitStruct.Pin = EN_12V_0_Pin|EN_12V_4_Pin|EN_12V_5_Pin;
  GPIO_InitStruct.Mode = GPIO_MODE_OUTPUT_PP;
  GPIO_InitStruct.Pull = GPIO_NOPULL;
  GPIO_InitStruct.Speed = GPIO_SPEED_FREQ_LOW;
  HAL_GPIO_Init(GPIOC, &GPIO_InitStruct);

  /*Configure GPIO pins : SDC_MCU_1_Pin SDC_MCU_2_Pin SDC_MCU_3_Pin SDC_MCU_4_Pin */
  GPIO_InitStruct.Pin = SDC_MCU_1_Pin|SDC_MCU_2_Pin|SDC_MCU_3_Pin|SDC_MCU_4_Pin;
  GPIO_InitStruct.Mode = GPIO_MODE_INPUT;
  GPIO_InitStruct.Pull = GPIO_NOPULL;
  HAL_GPIO_Init(GPIOE, &GPIO_InitStruct);

  /*Configure GPIO pin : USB_BUS_SNS_Pin */
  GPIO_InitStruct.Pin = USB_BUS_SNS_Pin;
  GPIO_InitStruct.Mode = GPIO_MODE_INPUT;
  GPIO_InitStruct.Pull = GPIO_NOPULL;
  HAL_GPIO_Init(USB_BUS_SNS_GPIO_Port, &GPIO_InitStruct);

  /*Configure GPIO pins : EN_12V_2_Pin EN_12V_3_Pin EN_12V_1_Pin USB_RESETB6_Pin
                           LED1_Pin PB8 PB9 */
  GPIO_InitStruct.Pin = EN_12V_2_Pin|EN_12V_3_Pin|EN_12V_1_Pin|USB_RESETB6_Pin
                          |LED1_Pin|GPIO_PIN_8|GPIO_PIN_9;
  GPIO_InitStruct.Mode = GPIO_MODE_OUTPUT_PP;
  GPIO_InitStruct.Pull = GPIO_NOPULL;
  GPIO_InitStruct.Speed = GPIO_SPEED_FREQ_LOW;
  HAL_GPIO_Init(GPIOB, &GPIO_InitStruct);

  /*Configure GPIO pins : LED_FAULT_Pin LED0_Pin RFD_GPIO3_Pin RPD_GPIO2_Pin
                           RFD_GPIO1_Pin */
  GPIO_InitStruct.Pin = LED_FAULT_Pin|LED0_Pin|RFD_GPIO3_Pin|RPD_GPIO2_Pin
                          |RFD_GPIO1_Pin;
  GPIO_InitStruct.Mode = GPIO_MODE_OUTPUT_PP;
  GPIO_InitStruct.Pull = GPIO_NOPULL;
  GPIO_InitStruct.Speed = GPIO_SPEED_FREQ_LOW;
  HAL_GPIO_Init(GPIOD, &GPIO_InitStruct);

  /*Configure GPIO pin : EN_12V_6_Pin */
  GPIO_InitStruct.Pin = EN_12V_6_Pin;
  GPIO_InitStruct.Mode = GPIO_MODE_OUTPUT_PP;
  GPIO_InitStruct.Pull = GPIO_NOPULL;
  GPIO_InitStruct.Speed = GPIO_SPEED_FREQ_LOW;
  HAL_GPIO_Init(EN_12V_6_GPIO_Port, &GPIO_InitStruct);

  /*Configure GPIO pin : SDIO_CD_Pin */
  GPIO_InitStruct.Pin = SDIO_CD_Pin;
  GPIO_InitStruct.Mode = GPIO_MODE_INPUT;
  GPIO_InitStruct.Pull = GPIO_NOPULL;
  HAL_GPIO_Init(SDIO_CD_GPIO_Port, &GPIO_InitStruct);

}

void plm_task_service_can(void const * argument)
{
  /* USER CODE BEGIN 5 */
  /* Infinite loop */
  for(;;)
  {
	  plm_service_can();
  }
  /* USER CODE END 5 */
}

void plm_task_store_data(void const * argument)
{
  /* USER CODE BEGIN plm_task_store_data */
  /* Infinite loop */
  for(;;)
  {
	  plm_store_data();
  }
  /* USER CODE END plm_task_store_data */
}

void plm_task_heartbeat(void const * argument)
{
  /* USER CODE BEGIN plm_task_heartbeat */
  /* Infinite loop */
  for(;;)
  {
	  plm_heartbeat();
    plm_sdc_sense();
  }
  /* USER CODE END plm_task_heartbeat */
}

void plm_task_simulate_data(void const * argument)
{
  /* USER CODE BEGIN plm_task_simulate_data */
  /* Infinite loop */
  for(;;)
  {
	  plm_simulate_data();
  }
  /* USER CODE END plm_task_simulate_data */
}

void plm_task_collect_data(void const * argument)
{
  /* USER CODE BEGIN plm_task_collect_data */
  /* Infinite loop */
  for(;;)
  {
	  plm_collect_data();
  }
  /* USER CODE END plm_task_collect_data */
}

void plm_task_monitor_current(void const * argument)
{
  /* USER CODE BEGIN plm_task_monitor_current */
  /* Infinite loop */
  for(;;)
  {
	  plm_monitor_current();
  }
  /* USER CODE END plm_task_monitor_current */
}

void HAL_TIM_PeriodElapsedCallback(TIM_HandleTypeDef *htim)
{
  if (htim->Instance == TIM6)
  {
    HAL_IncTick();
  }
}

void Error_Handler(void)
{
  __disable_irq();
  while (1)
  {
  }
}

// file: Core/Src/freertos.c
/* USER CODE BEGIN Header */
/**
  ******************************************************************************
  * File Name          : freertos.c
  * Description        : Code for freertos applications
  ******************************************************************************
  * @attention
  *
  * Copyright (c) 2024 STMicroelectronics.
  * All rights reserved.
  *
  * This software is licensed under terms that can be found in the LICENSE file
  * in the root directory of this software component.
  * If no LICENSE file comes with this software, it is provided AS-IS.
  *
  ******************************************************************************
  */
/* USER CODE END Header */

#include "FreeRTOS.h"
#include "task.h"
#include "main.h"
#include "cmsis_os.h"

osThreadId service_canHandle;
osThreadId store_dataHandle;
osThreadId plm_heartbeatHandle;
osThreadId simulate_dataHandle;
osThreadId collect_dataHandle;
osThreadId monitor_currentHandle;
osThreadId tm_heartbeatHandle;

void plm_task_service_can(void const * argument);
void plm_task_store_data(void const * argument);
void plm_task_heartbeat(void const * argument);
void plm_task_simulate_data(void const * argument);
void plm_task_collect_data(void const * argument);
void plm_task_monitor_current(void const * argument);
void tm_task_heartbeat(void const * argument);

void MX_FREERTOS_Init(void); /* (MISRA C 2004 rule 8.1) */

/* GetIdleTaskMemory prototype (linked to static allocation support) */
void vApplicationGetIdleTaskMemory( StaticTask_t **ppxIdleTaskTCBBuffer, StackType_t **ppxIdleTaskStackBuffer, uint32_t *pulIdleTaskStackSize );

/* USER CODE BEGIN GET_IDLE_TASK_MEMORY */
static StaticTask_t xIdleTaskTCBBuffer;
static StackType_t xIdleStack[configMINIMAL_STACK_SIZE];

void vApplicationGetIdleTaskMemory( StaticTask_t **ppxIdleTaskTCBBuffer, StackType_t **ppxIdleTaskStackBuffer, uint32_t *pulIdleTaskStackSize )
{
  *ppxIdleTaskTCBBuffer = &xIdleTaskTCBBuffer;
  *ppxIdleTaskStackBuffer = &xIdleStack[0];
  *pulIdleTaskStackSize = configMINIMAL_STACK_SIZE;
  /* place for user code */
}
/* USER CODE END GET_IDLE_TASK_MEMORY */

void MX_FREERTOS_Init(void) {

  /* Create the thread(s) */
  /* definition and creation of service_can */
  osThreadDef(service_can, plm_task_service_can, osPriorityNormal, 0, 1024);
  service_canHandle = osThreadCreate(osThread(service_can), NULL);

  /* definition and creation of store_data */
  osThreadDef(store_data, plm_task_store_data, osPriorityNormal, 0, 1024);
  store_dataHandle = osThreadCreate(osThread(store_data), NULL);

  /* definition and creation of plm_heartbeat */
  osThreadDef(plm_heartbeat, plm_task_heartbeat, osPriorityLow, 0, 512);
  plm_heartbeatHandle = osThreadCreate(osThread(plm_heartbeat), NULL);

  /* definition and creation of simulate_data */
  osThreadDef(simulate_data, plm_task_simulate_data, osPriorityLow, 0, 1024);
  simulate_dataHandle = osThreadCreate(osThread(simulate_data), NULL);

  /* definition and creation of collect_data */
  osThreadDef(collect_data, plm_task_collect_data, osPriorityNormal, 0, 1024);
  collect_dataHandle = osThreadCreate(osThread(collect_data), NULL);

  /* definition and creation of monitor_current */
  osThreadDef(monitor_current, plm_task_monitor_current, osPriorityNormal, 0, 1024);
  monitor_currentHandle = osThreadCreate(osThread(monitor_current), NULL);

  /* definition and creation of tm_heartbeat */
  osThreadDef(tm_heartbeat, tm_task_heartbeat, osPriorityLow, 0, 512);
  tm_heartbeatHandle = osThreadCreate(osThread(tm_heartbeat), NULL);

}

void plm_task_service_can(void const * argument)
{
  for(;;)
  {
    osDelay(1);
  }
}

void plm_task_store_data(void const * argument)
{
  for(;;)
  {
    osDelay(1);
  }
}

void plm_task_heartbeat(void const * argument)
{
  for(;;)
  {
    osDelay(1);
  }
}

void plm_task_simulate_data(void const * argument)
{
  for(;;)
  {
    osDelay(1);
  }
}

void plm_task_collect_data(void const * argument)
{
  for(;;)
  {
    osDelay(1);
  }
}

void plm_task_monitor_current(void const * argument)
{
  for(;;)
  {
    osDelay(1);
  }
}

void tm_task_heartbeat(void const * argument)
{
  for(;;)
  {
    osDelay(1);
  }
}
